VERSION 5.7 ;
BUSBITCHARS "[]" ;
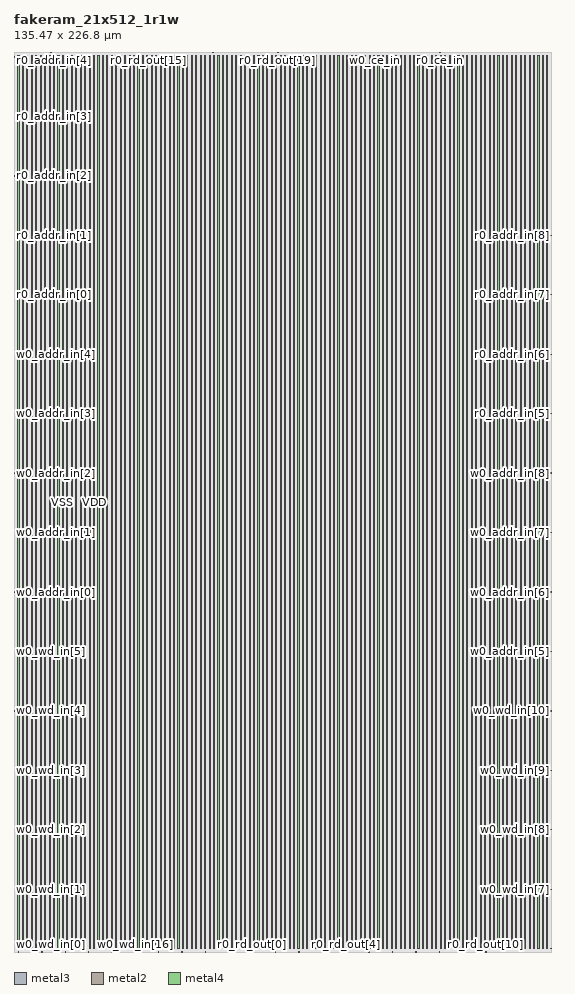
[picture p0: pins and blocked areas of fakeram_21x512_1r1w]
MACRO fakeram_21x512_1r1w
  FOREIGN fakeram_21x512_1r1w 0 0 ;
  SYMMETRY X Y R90 ;
  SIZE 135.470 BY 226.800 ;
  CLASS BLOCK ;
  PIN w0_wd_in[0]
    DIRECTION INPUT ;
    USE SIGNAL ;
    SHAPE ABUTMENT ;
    PORT
      LAYER metal3 ;
      RECT 0.000 0.805 0.210 0.875 ;
    END
  END w0_wd_in[0]
  PIN w0_wd_in[1]
    DIRECTION INPUT ;
    USE SIGNAL ;
    SHAPE ABUTMENT ;
    PORT
      LAYER metal3 ;
      RECT 0.000 15.785 0.210 15.855 ;
    END
  END w0_wd_in[1]
  PIN w0_wd_in[2]
    DIRECTION INPUT ;
    USE SIGNAL ;
    SHAPE ABUTMENT ;
    PORT
      LAYER metal3 ;
      RECT 0.000 30.765 0.210 30.835 ;
    END
  END w0_wd_in[2]
  PIN w0_wd_in[3]
    DIRECTION INPUT ;
    USE SIGNAL ;
    SHAPE ABUTMENT ;
    PORT
      LAYER metal3 ;
      RECT 0.000 45.745 0.210 45.815 ;
    END
  END w0_wd_in[3]
  PIN w0_wd_in[4]
    DIRECTION INPUT ;
    USE SIGNAL ;
    SHAPE ABUTMENT ;
    PORT
      LAYER metal3 ;
      RECT 0.000 60.725 0.210 60.795 ;
    END
  END w0_wd_in[4]
  PIN w0_wd_in[5]
    DIRECTION INPUT ;
    USE SIGNAL ;
    SHAPE ABUTMENT ;
    PORT
      LAYER metal3 ;
      RECT 0.000 75.705 0.210 75.775 ;
    END
  END w0_wd_in[5]
  PIN w0_wd_in[6]
    DIRECTION INPUT ;
    USE SIGNAL ;
    SHAPE ABUTMENT ;
    PORT
      LAYER metal3 ;
      RECT 135.260 0.805 135.470 0.875 ;
    END
  END w0_wd_in[6]
  PIN w0_wd_in[7]
    DIRECTION INPUT ;
    USE SIGNAL ;
    SHAPE ABUTMENT ;
    PORT
      LAYER metal3 ;
      RECT 135.260 15.785 135.470 15.855 ;
    END
  END w0_wd_in[7]
  PIN w0_wd_in[8]
    DIRECTION INPUT ;
    USE SIGNAL ;
    SHAPE ABUTMENT ;
    PORT
      LAYER metal3 ;
      RECT 135.260 30.765 135.470 30.835 ;
    END
  END w0_wd_in[8]
  PIN w0_wd_in[9]
    DIRECTION INPUT ;
    USE SIGNAL ;
    SHAPE ABUTMENT ;
    PORT
      LAYER metal3 ;
      RECT 135.260 45.745 135.470 45.815 ;
    END
  END w0_wd_in[9]
  PIN w0_wd_in[10]
    DIRECTION INPUT ;
    USE SIGNAL ;
    SHAPE ABUTMENT ;
    PORT
      LAYER metal3 ;
      RECT 135.260 60.725 135.470 60.795 ;
    END
  END w0_wd_in[10]
  PIN w0_wd_in[11]
    DIRECTION INPUT ;
    USE SIGNAL ;
    SHAPE ABUTMENT ;
    PORT
      LAYER metal2 ;
      RECT 1.105 0.000 1.175 0.210 ;
    END
  END w0_wd_in[11]
  PIN w0_wd_in[12]
    DIRECTION INPUT ;
    USE SIGNAL ;
    SHAPE ABUTMENT ;
    PORT
      LAYER metal2 ;
      RECT 6.995 0.000 7.065 0.210 ;
    END
  END w0_wd_in[12]
  PIN w0_wd_in[13]
    DIRECTION INPUT ;
    USE SIGNAL ;
    SHAPE ABUTMENT ;
    PORT
      LAYER metal2 ;
      RECT 12.885 0.000 12.955 0.210 ;
    END
  END w0_wd_in[13]
  PIN w0_wd_in[14]
    DIRECTION INPUT ;
    USE SIGNAL ;
    SHAPE ABUTMENT ;
    PORT
      LAYER metal2 ;
      RECT 18.775 0.000 18.845 0.210 ;
    END
  END w0_wd_in[14]
  PIN w0_wd_in[15]
    DIRECTION INPUT ;
    USE SIGNAL ;
    SHAPE ABUTMENT ;
    PORT
      LAYER metal2 ;
      RECT 24.665 0.000 24.735 0.210 ;
    END
  END w0_wd_in[15]
  PIN w0_wd_in[16]
    DIRECTION INPUT ;
    USE SIGNAL ;
    SHAPE ABUTMENT ;
    PORT
      LAYER metal2 ;
      RECT 30.555 0.000 30.625 0.210 ;
    END
  END w0_wd_in[16]
  PIN w0_wd_in[17]
    DIRECTION INPUT ;
    USE SIGNAL ;
    SHAPE ABUTMENT ;
    PORT
      LAYER metal2 ;
      RECT 36.445 0.000 36.515 0.210 ;
    END
  END w0_wd_in[17]
  PIN w0_wd_in[18]
    DIRECTION INPUT ;
    USE SIGNAL ;
    SHAPE ABUTMENT ;
    PORT
      LAYER metal2 ;
      RECT 42.335 0.000 42.405 0.210 ;
    END
  END w0_wd_in[18]
  PIN w0_wd_in[19]
    DIRECTION INPUT ;
    USE SIGNAL ;
    SHAPE ABUTMENT ;
    PORT
      LAYER metal2 ;
      RECT 48.225 0.000 48.295 0.210 ;
    END
  END w0_wd_in[19]
  PIN w0_wd_in[20]
    DIRECTION INPUT ;
    USE SIGNAL ;
    SHAPE ABUTMENT ;
    PORT
      LAYER metal2 ;
      RECT 54.115 0.000 54.185 0.210 ;
    END
  END w0_wd_in[20]
  PIN r0_rd_out[0]
    DIRECTION OUTPUT ;
    USE SIGNAL ;
    SHAPE ABUTMENT ;
    PORT
      LAYER metal2 ;
      RECT 60.005 0.000 60.075 0.210 ;
    END
  END r0_rd_out[0]
  PIN r0_rd_out[1]
    DIRECTION OUTPUT ;
    USE SIGNAL ;
    SHAPE ABUTMENT ;
    PORT
      LAYER metal2 ;
      RECT 65.895 0.000 65.965 0.210 ;
    END
  END r0_rd_out[1]
  PIN r0_rd_out[2]
    DIRECTION OUTPUT ;
    USE SIGNAL ;
    SHAPE ABUTMENT ;
    PORT
      LAYER metal2 ;
      RECT 71.785 0.000 71.855 0.210 ;
    END
  END r0_rd_out[2]
  PIN r0_rd_out[3]
    DIRECTION OUTPUT ;
    USE SIGNAL ;
    SHAPE ABUTMENT ;
    PORT
      LAYER metal2 ;
      RECT 77.675 0.000 77.745 0.210 ;
    END
  END r0_rd_out[3]
  PIN r0_rd_out[4]
    DIRECTION OUTPUT ;
    USE SIGNAL ;
    SHAPE ABUTMENT ;
    PORT
      LAYER metal2 ;
      RECT 83.565 0.000 83.635 0.210 ;
    END
  END r0_rd_out[4]
  PIN r0_rd_out[5]
    DIRECTION OUTPUT ;
    USE SIGNAL ;
    SHAPE ABUTMENT ;
    PORT
      LAYER metal2 ;
      RECT 89.455 0.000 89.525 0.210 ;
    END
  END r0_rd_out[5]
  PIN r0_rd_out[6]
    DIRECTION OUTPUT ;
    USE SIGNAL ;
    SHAPE ABUTMENT ;
    PORT
      LAYER metal2 ;
      RECT 95.345 0.000 95.415 0.210 ;
    END
  END r0_rd_out[6]
  PIN r0_rd_out[7]
    DIRECTION OUTPUT ;
    USE SIGNAL ;
    SHAPE ABUTMENT ;
    PORT
      LAYER metal2 ;
      RECT 101.235 0.000 101.305 0.210 ;
    END
  END r0_rd_out[7]
  PIN r0_rd_out[8]
    DIRECTION OUTPUT ;
    USE SIGNAL ;
    SHAPE ABUTMENT ;
    PORT
      LAYER metal2 ;
      RECT 107.125 0.000 107.195 0.210 ;
    END
  END r0_rd_out[8]
  PIN r0_rd_out[9]
    DIRECTION OUTPUT ;
    USE SIGNAL ;
    SHAPE ABUTMENT ;
    PORT
      LAYER metal2 ;
      RECT 113.015 0.000 113.085 0.210 ;
    END
  END r0_rd_out[9]
  PIN r0_rd_out[10]
    DIRECTION OUTPUT ;
    USE SIGNAL ;
    SHAPE ABUTMENT ;
    PORT
      LAYER metal2 ;
      RECT 118.905 0.000 118.975 0.210 ;
    END
  END r0_rd_out[10]
  PIN r0_rd_out[11]
    DIRECTION OUTPUT ;
    USE SIGNAL ;
    SHAPE ABUTMENT ;
    PORT
      LAYER metal2 ;
      RECT 1.105 226.590 1.175 226.800 ;
    END
  END r0_rd_out[11]
  PIN r0_rd_out[12]
    DIRECTION OUTPUT ;
    USE SIGNAL ;
    SHAPE ABUTMENT ;
    PORT
      LAYER metal2 ;
      RECT 9.275 226.590 9.345 226.800 ;
    END
  END r0_rd_out[12]
  PIN r0_rd_out[13]
    DIRECTION OUTPUT ;
    USE SIGNAL ;
    SHAPE ABUTMENT ;
    PORT
      LAYER metal2 ;
      RECT 17.445 226.590 17.515 226.800 ;
    END
  END r0_rd_out[13]
  PIN r0_rd_out[14]
    DIRECTION OUTPUT ;
    USE SIGNAL ;
    SHAPE ABUTMENT ;
    PORT
      LAYER metal2 ;
      RECT 25.615 226.590 25.685 226.800 ;
    END
  END r0_rd_out[14]
  PIN r0_rd_out[15]
    DIRECTION OUTPUT ;
    USE SIGNAL ;
    SHAPE ABUTMENT ;
    PORT
      LAYER metal2 ;
      RECT 33.785 226.590 33.855 226.800 ;
    END
  END r0_rd_out[15]
  PIN r0_rd_out[16]
    DIRECTION OUTPUT ;
    USE SIGNAL ;
    SHAPE ABUTMENT ;
    PORT
      LAYER metal2 ;
      RECT 41.955 226.590 42.025 226.800 ;
    END
  END r0_rd_out[16]
  PIN r0_rd_out[17]
    DIRECTION OUTPUT ;
    USE SIGNAL ;
    SHAPE ABUTMENT ;
    PORT
      LAYER metal2 ;
      RECT 50.125 226.590 50.195 226.800 ;
    END
  END r0_rd_out[17]
  PIN r0_rd_out[18]
    DIRECTION OUTPUT ;
    USE SIGNAL ;
    SHAPE ABUTMENT ;
    PORT
      LAYER metal2 ;
      RECT 58.295 226.590 58.365 226.800 ;
    END
  END r0_rd_out[18]
  PIN r0_rd_out[19]
    DIRECTION OUTPUT ;
    USE SIGNAL ;
    SHAPE ABUTMENT ;
    PORT
      LAYER metal2 ;
      RECT 66.465 226.590 66.535 226.800 ;
    END
  END r0_rd_out[19]
  PIN r0_rd_out[20]
    DIRECTION OUTPUT ;
    USE SIGNAL ;
    SHAPE ABUTMENT ;
    PORT
      LAYER metal2 ;
      RECT 74.635 226.590 74.705 226.800 ;
    END
  END r0_rd_out[20]
  PIN w0_addr_in[0]
    DIRECTION INPUT ;
    USE SIGNAL ;
    SHAPE ABUTMENT ;
    PORT
      LAYER metal3 ;
      RECT 0.000 90.685 0.210 90.755 ;
    END
  END w0_addr_in[0]
  PIN w0_addr_in[1]
    DIRECTION INPUT ;
    USE SIGNAL ;
    SHAPE ABUTMENT ;
    PORT
      LAYER metal3 ;
      RECT 0.000 105.665 0.210 105.735 ;
    END
  END w0_addr_in[1]
  PIN w0_addr_in[2]
    DIRECTION INPUT ;
    USE SIGNAL ;
    SHAPE ABUTMENT ;
    PORT
      LAYER metal3 ;
      RECT 0.000 120.645 0.210 120.715 ;
    END
  END w0_addr_in[2]
  PIN w0_addr_in[3]
    DIRECTION INPUT ;
    USE SIGNAL ;
    SHAPE ABUTMENT ;
    PORT
      LAYER metal3 ;
      RECT 0.000 135.625 0.210 135.695 ;
    END
  END w0_addr_in[3]
  PIN w0_addr_in[4]
    DIRECTION INPUT ;
    USE SIGNAL ;
    SHAPE ABUTMENT ;
    PORT
      LAYER metal3 ;
      RECT 0.000 150.605 0.210 150.675 ;
    END
  END w0_addr_in[4]
  PIN w0_addr_in[5]
    DIRECTION INPUT ;
    USE SIGNAL ;
    SHAPE ABUTMENT ;
    PORT
      LAYER metal3 ;
      RECT 135.260 75.705 135.470 75.775 ;
    END
  END w0_addr_in[5]
  PIN w0_addr_in[6]
    DIRECTION INPUT ;
    USE SIGNAL ;
    SHAPE ABUTMENT ;
    PORT
      LAYER metal3 ;
      RECT 135.260 90.685 135.470 90.755 ;
    END
  END w0_addr_in[6]
  PIN w0_addr_in[7]
    DIRECTION INPUT ;
    USE SIGNAL ;
    SHAPE ABUTMENT ;
    PORT
      LAYER metal3 ;
      RECT 135.260 105.665 135.470 105.735 ;
    END
  END w0_addr_in[7]
  PIN w0_addr_in[8]
    DIRECTION INPUT ;
    USE SIGNAL ;
    SHAPE ABUTMENT ;
    PORT
      LAYER metal3 ;
      RECT 135.260 120.645 135.470 120.715 ;
    END
  END w0_addr_in[8]
  PIN r0_addr_in[0]
    DIRECTION INPUT ;
    USE SIGNAL ;
    SHAPE ABUTMENT ;
    PORT
      LAYER metal3 ;
      RECT 0.000 165.585 0.210 165.655 ;
    END
  END r0_addr_in[0]
  PIN r0_addr_in[1]
    DIRECTION INPUT ;
    USE SIGNAL ;
    SHAPE ABUTMENT ;
    PORT
      LAYER metal3 ;
      RECT 0.000 180.565 0.210 180.635 ;
    END
  END r0_addr_in[1]
  PIN r0_addr_in[2]
    DIRECTION INPUT ;
    USE SIGNAL ;
    SHAPE ABUTMENT ;
    PORT
      LAYER metal3 ;
      RECT 0.000 195.545 0.210 195.615 ;
    END
  END r0_addr_in[2]
  PIN r0_addr_in[3]
    DIRECTION INPUT ;
    USE SIGNAL ;
    SHAPE ABUTMENT ;
    PORT
      LAYER metal3 ;
      RECT 0.000 210.525 0.210 210.595 ;
    END
  END r0_addr_in[3]
  PIN r0_addr_in[4]
    DIRECTION INPUT ;
    USE SIGNAL ;
    SHAPE ABUTMENT ;
    PORT
      LAYER metal3 ;
      RECT 0.000 225.505 0.210 225.575 ;
    END
  END r0_addr_in[4]
  PIN r0_addr_in[5]
    DIRECTION INPUT ;
    USE SIGNAL ;
    SHAPE ABUTMENT ;
    PORT
      LAYER metal3 ;
      RECT 135.260 135.625 135.470 135.695 ;
    END
  END r0_addr_in[5]
  PIN r0_addr_in[6]
    DIRECTION INPUT ;
    USE SIGNAL ;
    SHAPE ABUTMENT ;
    PORT
      LAYER metal3 ;
      RECT 135.260 150.605 135.470 150.675 ;
    END
  END r0_addr_in[6]
  PIN r0_addr_in[7]
    DIRECTION INPUT ;
    USE SIGNAL ;
    SHAPE ABUTMENT ;
    PORT
      LAYER metal3 ;
      RECT 135.260 165.585 135.470 165.655 ;
    END
  END r0_addr_in[7]
  PIN r0_addr_in[8]
    DIRECTION INPUT ;
    USE SIGNAL ;
    SHAPE ABUTMENT ;
    PORT
      LAYER metal3 ;
      RECT 135.260 180.565 135.470 180.635 ;
    END
  END r0_addr_in[8]
  PIN w0_we_in
    DIRECTION INPUT ;
    USE SIGNAL ;
    SHAPE ABUTMENT ;
    PORT
      LAYER metal2 ;
      RECT 82.805 226.590 82.875 226.800 ;
    END
  END w0_we_in
  PIN w0_ce_in
    DIRECTION INPUT ;
    USE SIGNAL ;
    SHAPE ABUTMENT ;
    PORT
      LAYER metal2 ;
      RECT 90.975 226.590 91.045 226.800 ;
    END
  END w0_ce_in
  PIN w0_clk
    DIRECTION INPUT ;
    USE SIGNAL ;
    SHAPE ABUTMENT ;
    PORT
      LAYER metal2 ;
      RECT 99.145 226.590 99.215 226.800 ;
    END
  END w0_clk
  PIN r0_ce_in
    DIRECTION INPUT ;
    USE SIGNAL ;
    SHAPE ABUTMENT ;
    PORT
      LAYER metal2 ;
      RECT 107.315 226.590 107.385 226.800 ;
    END
  END r0_ce_in
  PIN r0_clk
    DIRECTION INPUT ;
    USE SIGNAL ;
    SHAPE ABUTMENT ;
    PORT
      LAYER metal2 ;
      RECT 115.485 226.590 115.555 226.800 ;
    END
  END r0_clk
  PIN VSS
    DIRECTION INOUT ;
    USE GROUND ;
    PORT
      LAYER metal4 ;
      RECT 1.000 0.840 1.280 225.960 ;
      RECT 3.240 0.840 3.520 225.960 ;
      RECT 5.480 0.840 5.760 225.960 ;
      RECT 7.720 0.840 8.000 225.960 ;
      RECT 9.960 0.840 10.240 225.960 ;
      RECT 12.200 0.840 12.480 225.960 ;
      RECT 14.440 0.840 14.720 225.960 ;
      RECT 16.680 0.840 16.960 225.960 ;
      RECT 18.920 0.840 19.200 225.960 ;
      RECT 21.160 0.840 21.440 225.960 ;
      RECT 23.400 0.840 23.680 225.960 ;
      RECT 25.640 0.840 25.920 225.960 ;
      RECT 27.880 0.840 28.160 225.960 ;
      RECT 30.120 0.840 30.400 225.960 ;
      RECT 32.360 0.840 32.640 225.960 ;
      RECT 34.600 0.840 34.880 225.960 ;
      RECT 36.840 0.840 37.120 225.960 ;
      RECT 39.080 0.840 39.360 225.960 ;
      RECT 41.320 0.840 41.600 225.960 ;
      RECT 43.560 0.840 43.840 225.960 ;
      RECT 45.800 0.840 46.080 225.960 ;
      RECT 48.040 0.840 48.320 225.960 ;
      RECT 50.280 0.840 50.560 225.960 ;
      RECT 52.520 0.840 52.800 225.960 ;
      RECT 54.760 0.840 55.040 225.960 ;
      RECT 57.000 0.840 57.280 225.960 ;
      RECT 59.240 0.840 59.520 225.960 ;
      RECT 61.480 0.840 61.760 225.960 ;
      RECT 63.720 0.840 64.000 225.960 ;
      RECT 65.960 0.840 66.240 225.960 ;
      RECT 68.200 0.840 68.480 225.960 ;
      RECT 70.440 0.840 70.720 225.960 ;
      RECT 72.680 0.840 72.960 225.960 ;
      RECT 74.920 0.840 75.200 225.960 ;
      RECT 77.160 0.840 77.440 225.960 ;
      RECT 79.400 0.840 79.680 225.960 ;
      RECT 81.640 0.840 81.920 225.960 ;
      RECT 83.880 0.840 84.160 225.960 ;
      RECT 86.120 0.840 86.400 225.960 ;
      RECT 88.360 0.840 88.640 225.960 ;
      RECT 90.600 0.840 90.880 225.960 ;
      RECT 92.840 0.840 93.120 225.960 ;
      RECT 95.080 0.840 95.360 225.960 ;
      RECT 97.320 0.840 97.600 225.960 ;
      RECT 99.560 0.840 99.840 225.960 ;
      RECT 101.800 0.840 102.080 225.960 ;
      RECT 104.040 0.840 104.320 225.960 ;
      RECT 106.280 0.840 106.560 225.960 ;
      RECT 108.520 0.840 108.800 225.960 ;
      RECT 110.760 0.840 111.040 225.960 ;
      RECT 113.000 0.840 113.280 225.960 ;
      RECT 115.240 0.840 115.520 225.960 ;
      RECT 117.480 0.840 117.760 225.960 ;
      RECT 119.720 0.840 120.000 225.960 ;
      RECT 121.960 0.840 122.240 225.960 ;
      RECT 124.200 0.840 124.480 225.960 ;
      RECT 126.440 0.840 126.720 225.960 ;
      RECT 128.680 0.840 128.960 225.960 ;
      RECT 130.920 0.840 131.200 225.960 ;
      RECT 133.160 0.840 133.440 225.960 ;
    END
  END VSS
  PIN VDD
    DIRECTION INOUT ;
    USE POWER ;
    PORT
      LAYER metal4 ;
      RECT 2.120 0.840 2.400 225.960 ;
      RECT 4.360 0.840 4.640 225.960 ;
      RECT 6.600 0.840 6.880 225.960 ;
      RECT 8.840 0.840 9.120 225.960 ;
      RECT 11.080 0.840 11.360 225.960 ;
      RECT 13.320 0.840 13.600 225.960 ;
      RECT 15.560 0.840 15.840 225.960 ;
      RECT 17.800 0.840 18.080 225.960 ;
      RECT 20.040 0.840 20.320 225.960 ;
      RECT 22.280 0.840 22.560 225.960 ;
      RECT 24.520 0.840 24.800 225.960 ;
      RECT 26.760 0.840 27.040 225.960 ;
      RECT 29.000 0.840 29.280 225.960 ;
      RECT 31.240 0.840 31.520 225.960 ;
      RECT 33.480 0.840 33.760 225.960 ;
      RECT 35.720 0.840 36.000 225.960 ;
      RECT 37.960 0.840 38.240 225.960 ;
      RECT 40.200 0.840 40.480 225.960 ;
      RECT 42.440 0.840 42.720 225.960 ;
      RECT 44.680 0.840 44.960 225.960 ;
      RECT 46.920 0.840 47.200 225.960 ;
      RECT 49.160 0.840 49.440 225.960 ;
      RECT 51.400 0.840 51.680 225.960 ;
      RECT 53.640 0.840 53.920 225.960 ;
      RECT 55.880 0.840 56.160 225.960 ;
      RECT 58.120 0.840 58.400 225.960 ;
      RECT 60.360 0.840 60.640 225.960 ;
      RECT 62.600 0.840 62.880 225.960 ;
      RECT 64.840 0.840 65.120 225.960 ;
      RECT 67.080 0.840 67.360 225.960 ;
      RECT 69.320 0.840 69.600 225.960 ;
      RECT 71.560 0.840 71.840 225.960 ;
      RECT 73.800 0.840 74.080 225.960 ;
      RECT 76.040 0.840 76.320 225.960 ;
      RECT 78.280 0.840 78.560 225.960 ;
      RECT 80.520 0.840 80.800 225.960 ;
      RECT 82.760 0.840 83.040 225.960 ;
      RECT 85.000 0.840 85.280 225.960 ;
      RECT 87.240 0.840 87.520 225.960 ;
      RECT 89.480 0.840 89.760 225.960 ;
      RECT 91.720 0.840 92.000 225.960 ;
      RECT 93.960 0.840 94.240 225.960 ;
      RECT 96.200 0.840 96.480 225.960 ;
      RECT 98.440 0.840 98.720 225.960 ;
      RECT 100.680 0.840 100.960 225.960 ;
      RECT 102.920 0.840 103.200 225.960 ;
      RECT 105.160 0.840 105.440 225.960 ;
      RECT 107.400 0.840 107.680 225.960 ;
      RECT 109.640 0.840 109.920 225.960 ;
      RECT 111.880 0.840 112.160 225.960 ;
      RECT 114.120 0.840 114.400 225.960 ;
      RECT 116.360 0.840 116.640 225.960 ;
      RECT 118.600 0.840 118.880 225.960 ;
      RECT 120.840 0.840 121.120 225.960 ;
      RECT 123.080 0.840 123.360 225.960 ;
      RECT 125.320 0.840 125.600 225.960 ;
      RECT 127.560 0.840 127.840 225.960 ;
      RECT 129.800 0.840 130.080 225.960 ;
      RECT 132.040 0.840 132.320 225.960 ;
      RECT 134.280 0.840 134.560 225.960 ;
    END
  END VDD
  OBS
    LAYER metal1 ;
    RECT 0 0 135.470 226.800 ;
    LAYER metal2 ;
    RECT 0 0 135.470 226.800 ;
    LAYER metal3 ;
    RECT 0 0 135.470 226.800 ;
    LAYER metal4 ;
    RECT 0 0 135.470 226.800 ;
    LAYER OVERLAP ;
    RECT 0 0 135.470 226.800 ;
  END
END fakeram_21x512_1r1w

END LIBRARY
